VERSION 5.7 ;
BUSBITCHARS "[]" ;
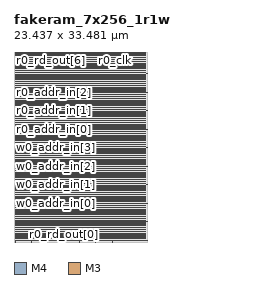
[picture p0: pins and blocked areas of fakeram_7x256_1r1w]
MACRO fakeram_7x256_1r1w
  FOREIGN fakeram_7x256_1r1w 0 0 ;
  SYMMETRY X Y R90 ;
  SIZE 23.437 BY 33.481 ;
  CLASS BLOCK ;
  PIN w0_wd_in[0]
    DIRECTION INPUT ;
    USE SIGNAL ;
    SHAPE ABUTMENT ;
    PORT
      LAYER M4 ;
      RECT 0.000 0.276 0.072 0.300 ;
    END
  END w0_wd_in[0]
  PIN w0_wd_in[1]
    DIRECTION INPUT ;
    USE SIGNAL ;
    SHAPE ABUTMENT ;
    PORT
      LAYER M4 ;
      RECT 0.000 3.540 0.072 3.564 ;
    END
  END w0_wd_in[1]
  PIN w0_wd_in[2]
    DIRECTION INPUT ;
    USE SIGNAL ;
    SHAPE ABUTMENT ;
    PORT
      LAYER M4 ;
      RECT 23.365 0.276 23.437 0.300 ;
    END
  END w0_wd_in[2]
  PIN w0_wd_in[3]
    DIRECTION INPUT ;
    USE SIGNAL ;
    SHAPE ABUTMENT ;
    PORT
      LAYER M4 ;
      RECT 23.365 3.540 23.437 3.564 ;
    END
  END w0_wd_in[3]
  PIN w0_wd_in[4]
    DIRECTION INPUT ;
    USE SIGNAL ;
    SHAPE ABUTMENT ;
    PORT
      LAYER M3 ;
      RECT 0.207 0.000 0.225 0.054 ;
    END
  END w0_wd_in[4]
  PIN w0_wd_in[5]
    DIRECTION INPUT ;
    USE SIGNAL ;
    SHAPE ABUTMENT ;
    PORT
      LAYER M3 ;
      RECT 3.051 0.000 3.069 0.054 ;
    END
  END w0_wd_in[5]
  PIN w0_wd_in[6]
    DIRECTION INPUT ;
    USE SIGNAL ;
    SHAPE ABUTMENT ;
    PORT
      LAYER M3 ;
      RECT 5.895 0.000 5.913 0.054 ;
    END
  END w0_wd_in[6]
  PIN r0_rd_out[0]
    DIRECTION OUTPUT ;
    USE SIGNAL ;
    SHAPE ABUTMENT ;
    PORT
      LAYER M3 ;
      RECT 8.739 0.000 8.757 0.054 ;
    END
  END r0_rd_out[0]
  PIN r0_rd_out[1]
    DIRECTION OUTPUT ;
    USE SIGNAL ;
    SHAPE ABUTMENT ;
    PORT
      LAYER M3 ;
      RECT 11.583 0.000 11.601 0.054 ;
    END
  END r0_rd_out[1]
  PIN r0_rd_out[2]
    DIRECTION OUTPUT ;
    USE SIGNAL ;
    SHAPE ABUTMENT ;
    PORT
      LAYER M3 ;
      RECT 14.427 0.000 14.445 0.054 ;
    END
  END r0_rd_out[2]
  PIN r0_rd_out[3]
    DIRECTION OUTPUT ;
    USE SIGNAL ;
    SHAPE ABUTMENT ;
    PORT
      LAYER M3 ;
      RECT 17.271 0.000 17.289 0.054 ;
    END
  END r0_rd_out[3]
  PIN r0_rd_out[4]
    DIRECTION OUTPUT ;
    USE SIGNAL ;
    SHAPE ABUTMENT ;
    PORT
      LAYER M3 ;
      RECT 0.207 33.427 0.225 33.481 ;
    END
  END r0_rd_out[4]
  PIN r0_rd_out[5]
    DIRECTION OUTPUT ;
    USE SIGNAL ;
    SHAPE ABUTMENT ;
    PORT
      LAYER M3 ;
      RECT 2.727 33.427 2.745 33.481 ;
    END
  END r0_rd_out[5]
  PIN r0_rd_out[6]
    DIRECTION OUTPUT ;
    USE SIGNAL ;
    SHAPE ABUTMENT ;
    PORT
      LAYER M3 ;
      RECT 5.247 33.427 5.265 33.481 ;
    END
  END r0_rd_out[6]
  PIN w0_addr_in[0]
    DIRECTION INPUT ;
    USE SIGNAL ;
    SHAPE ABUTMENT ;
    PORT
      LAYER M4 ;
      RECT 0.000 6.804 0.072 6.828 ;
    END
  END w0_addr_in[0]
  PIN w0_addr_in[1]
    DIRECTION INPUT ;
    USE SIGNAL ;
    SHAPE ABUTMENT ;
    PORT
      LAYER M4 ;
      RECT 0.000 10.068 0.072 10.092 ;
    END
  END w0_addr_in[1]
  PIN w0_addr_in[2]
    DIRECTION INPUT ;
    USE SIGNAL ;
    SHAPE ABUTMENT ;
    PORT
      LAYER M4 ;
      RECT 0.000 13.332 0.072 13.356 ;
    END
  END w0_addr_in[2]
  PIN w0_addr_in[3]
    DIRECTION INPUT ;
    USE SIGNAL ;
    SHAPE ABUTMENT ;
    PORT
      LAYER M4 ;
      RECT 0.000 16.596 0.072 16.620 ;
    END
  END w0_addr_in[3]
  PIN w0_addr_in[4]
    DIRECTION INPUT ;
    USE SIGNAL ;
    SHAPE ABUTMENT ;
    PORT
      LAYER M4 ;
      RECT 23.365 6.804 23.437 6.828 ;
    END
  END w0_addr_in[4]
  PIN w0_addr_in[5]
    DIRECTION INPUT ;
    USE SIGNAL ;
    SHAPE ABUTMENT ;
    PORT
      LAYER M4 ;
      RECT 23.365 10.068 23.437 10.092 ;
    END
  END w0_addr_in[5]
  PIN w0_addr_in[6]
    DIRECTION INPUT ;
    USE SIGNAL ;
    SHAPE ABUTMENT ;
    PORT
      LAYER M4 ;
      RECT 23.365 13.332 23.437 13.356 ;
    END
  END w0_addr_in[6]
  PIN w0_addr_in[7]
    DIRECTION INPUT ;
    USE SIGNAL ;
    SHAPE ABUTMENT ;
    PORT
      LAYER M4 ;
      RECT 23.365 16.596 23.437 16.620 ;
    END
  END w0_addr_in[7]
  PIN r0_addr_in[0]
    DIRECTION INPUT ;
    USE SIGNAL ;
    SHAPE ABUTMENT ;
    PORT
      LAYER M4 ;
      RECT 0.000 19.860 0.072 19.884 ;
    END
  END r0_addr_in[0]
  PIN r0_addr_in[1]
    DIRECTION INPUT ;
    USE SIGNAL ;
    SHAPE ABUTMENT ;
    PORT
      LAYER M4 ;
      RECT 0.000 23.124 0.072 23.148 ;
    END
  END r0_addr_in[1]
  PIN r0_addr_in[2]
    DIRECTION INPUT ;
    USE SIGNAL ;
    SHAPE ABUTMENT ;
    PORT
      LAYER M4 ;
      RECT 0.000 26.388 0.072 26.412 ;
    END
  END r0_addr_in[2]
  PIN r0_addr_in[3]
    DIRECTION INPUT ;
    USE SIGNAL ;
    SHAPE ABUTMENT ;
    PORT
      LAYER M4 ;
      RECT 0.000 29.652 0.072 29.676 ;
    END
  END r0_addr_in[3]
  PIN r0_addr_in[4]
    DIRECTION INPUT ;
    USE SIGNAL ;
    SHAPE ABUTMENT ;
    PORT
      LAYER M4 ;
      RECT 23.365 19.860 23.437 19.884 ;
    END
  END r0_addr_in[4]
  PIN r0_addr_in[5]
    DIRECTION INPUT ;
    USE SIGNAL ;
    SHAPE ABUTMENT ;
    PORT
      LAYER M4 ;
      RECT 23.365 23.124 23.437 23.148 ;
    END
  END r0_addr_in[5]
  PIN r0_addr_in[6]
    DIRECTION INPUT ;
    USE SIGNAL ;
    SHAPE ABUTMENT ;
    PORT
      LAYER M4 ;
      RECT 23.365 26.388 23.437 26.412 ;
    END
  END r0_addr_in[6]
  PIN r0_addr_in[7]
    DIRECTION INPUT ;
    USE SIGNAL ;
    SHAPE ABUTMENT ;
    PORT
      LAYER M4 ;
      RECT 23.365 29.652 23.437 29.676 ;
    END
  END r0_addr_in[7]
  PIN w0_we_in
    DIRECTION INPUT ;
    USE SIGNAL ;
    SHAPE ABUTMENT ;
    PORT
      LAYER M3 ;
      RECT 7.767 33.427 7.785 33.481 ;
    END
  END w0_we_in
  PIN w0_ce_in
    DIRECTION INPUT ;
    USE SIGNAL ;
    SHAPE ABUTMENT ;
    PORT
      LAYER M3 ;
      RECT 10.287 33.427 10.305 33.481 ;
    END
  END w0_ce_in
  PIN w0_clk
    DIRECTION INPUT ;
    USE SIGNAL ;
    SHAPE ABUTMENT ;
    PORT
      LAYER M3 ;
      RECT 12.807 33.427 12.825 33.481 ;
    END
  END w0_clk
  PIN r0_ce_in
    DIRECTION INPUT ;
    USE SIGNAL ;
    SHAPE ABUTMENT ;
    PORT
      LAYER M3 ;
      RECT 15.327 33.427 15.345 33.481 ;
    END
  END r0_ce_in
  PIN r0_clk
    DIRECTION INPUT ;
    USE SIGNAL ;
    SHAPE ABUTMENT ;
    PORT
      LAYER M3 ;
      RECT 17.847 33.427 17.865 33.481 ;
    END
  END r0_clk
  PIN VSS
    DIRECTION INOUT ;
    USE GROUND ;
    PORT
      LAYER M4 ;
      RECT 0.216 0.240 23.221 0.336 ;
      RECT 0.216 1.008 23.221 1.104 ;
      RECT 0.216 1.776 23.221 1.872 ;
      RECT 0.216 2.544 23.221 2.640 ;
      RECT 0.216 3.312 23.221 3.408 ;
      RECT 0.216 4.080 23.221 4.176 ;
      RECT 0.216 4.848 23.221 4.944 ;
      RECT 0.216 5.616 23.221 5.712 ;
      RECT 0.216 6.384 23.221 6.480 ;
      RECT 0.216 7.152 23.221 7.248 ;
      RECT 0.216 7.920 23.221 8.016 ;
      RECT 0.216 8.688 23.221 8.784 ;
      RECT 0.216 9.456 23.221 9.552 ;
      RECT 0.216 10.224 23.221 10.320 ;
      RECT 0.216 10.992 23.221 11.088 ;
      RECT 0.216 11.760 23.221 11.856 ;
      RECT 0.216 12.528 23.221 12.624 ;
      RECT 0.216 13.296 23.221 13.392 ;
      RECT 0.216 14.064 23.221 14.160 ;
      RECT 0.216 14.832 23.221 14.928 ;
      RECT 0.216 15.600 23.221 15.696 ;
      RECT 0.216 16.368 23.221 16.464 ;
      RECT 0.216 17.136 23.221 17.232 ;
      RECT 0.216 17.904 23.221 18.000 ;
      RECT 0.216 18.672 23.221 18.768 ;
      RECT 0.216 19.440 23.221 19.536 ;
      RECT 0.216 20.208 23.221 20.304 ;
      RECT 0.216 20.976 23.221 21.072 ;
      RECT 0.216 21.744 23.221 21.840 ;
      RECT 0.216 22.512 23.221 22.608 ;
      RECT 0.216 23.280 23.221 23.376 ;
      RECT 0.216 24.048 23.221 24.144 ;
      RECT 0.216 24.816 23.221 24.912 ;
      RECT 0.216 25.584 23.221 25.680 ;
      RECT 0.216 26.352 23.221 26.448 ;
      RECT 0.216 27.120 23.221 27.216 ;
      RECT 0.216 27.888 23.221 27.984 ;
      RECT 0.216 28.656 23.221 28.752 ;
      RECT 0.216 29.424 23.221 29.520 ;
      RECT 0.216 30.192 23.221 30.288 ;
      RECT 0.216 30.960 23.221 31.056 ;
      RECT 0.216 31.728 23.221 31.824 ;
      RECT 0.216 32.496 23.221 32.592 ;
      RECT 0.216 33.264 23.221 33.360 ;
    END
  END VSS
  PIN VDD
    DIRECTION INOUT ;
    USE POWER ;
    PORT
      LAYER M4 ;
      RECT 0.216 0.624 23.221 0.720 ;
      RECT 0.216 1.392 23.221 1.488 ;
      RECT 0.216 2.160 23.221 2.256 ;
      RECT 0.216 2.928 23.221 3.024 ;
      RECT 0.216 3.696 23.221 3.792 ;
      RECT 0.216 4.464 23.221 4.560 ;
      RECT 0.216 5.232 23.221 5.328 ;
      RECT 0.216 6.000 23.221 6.096 ;
      RECT 0.216 6.768 23.221 6.864 ;
      RECT 0.216 7.536 23.221 7.632 ;
      RECT 0.216 8.304 23.221 8.400 ;
      RECT 0.216 9.072 23.221 9.168 ;
      RECT 0.216 9.840 23.221 9.936 ;
      RECT 0.216 10.608 23.221 10.704 ;
      RECT 0.216 11.376 23.221 11.472 ;
      RECT 0.216 12.144 23.221 12.240 ;
      RECT 0.216 12.912 23.221 13.008 ;
      RECT 0.216 13.680 23.221 13.776 ;
      RECT 0.216 14.448 23.221 14.544 ;
      RECT 0.216 15.216 23.221 15.312 ;
      RECT 0.216 15.984 23.221 16.080 ;
      RECT 0.216 16.752 23.221 16.848 ;
      RECT 0.216 17.520 23.221 17.616 ;
      RECT 0.216 18.288 23.221 18.384 ;
      RECT 0.216 19.056 23.221 19.152 ;
      RECT 0.216 19.824 23.221 19.920 ;
      RECT 0.216 20.592 23.221 20.688 ;
      RECT 0.216 21.360 23.221 21.456 ;
      RECT 0.216 22.128 23.221 22.224 ;
      RECT 0.216 22.896 23.221 22.992 ;
      RECT 0.216 23.664 23.221 23.760 ;
      RECT 0.216 24.432 23.221 24.528 ;
      RECT 0.216 25.200 23.221 25.296 ;
      RECT 0.216 25.968 23.221 26.064 ;
      RECT 0.216 26.736 23.221 26.832 ;
      RECT 0.216 27.504 23.221 27.600 ;
      RECT 0.216 28.272 23.221 28.368 ;
      RECT 0.216 29.040 23.221 29.136 ;
      RECT 0.216 29.808 23.221 29.904 ;
      RECT 0.216 30.576 23.221 30.672 ;
      RECT 0.216 31.344 23.221 31.440 ;
      RECT 0.216 32.112 23.221 32.208 ;
      RECT 0.216 32.880 23.221 32.976 ;
    END
  END VDD
  OBS
    LAYER M1 ;
    RECT 0 0 23.437 33.481 ;
    LAYER M2 ;
    RECT 0 0 23.437 33.481 ;
    LAYER M3 ;
    RECT 0 0 23.437 33.481 ;
    LAYER M4 ;
    RECT 0 0 23.437 33.481 ;
  END
END fakeram_7x256_1r1w

END LIBRARY
